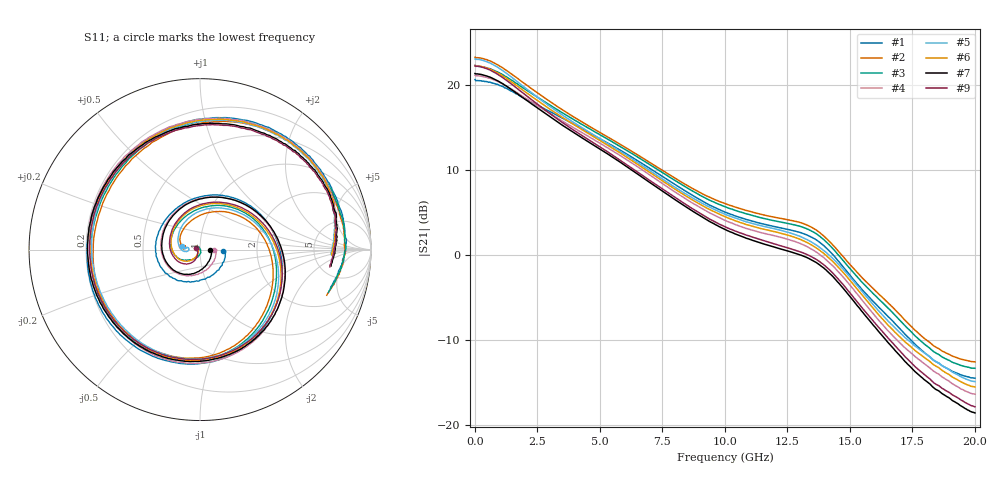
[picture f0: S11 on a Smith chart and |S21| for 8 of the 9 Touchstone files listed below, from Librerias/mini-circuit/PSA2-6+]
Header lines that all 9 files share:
!Keysight Technologies,N5242A,MY47200155,A.10.49.08
!Correction: S11(Full 2 Port(1,2))
!S21(Full 2 Port(1,2))
!S12(Full 2 Port(1,2))
!S22(Full 2 Port(1,2))
!S2P File: Measurements: S11, S21, S12, S22:
# Hz S  dB  R 50
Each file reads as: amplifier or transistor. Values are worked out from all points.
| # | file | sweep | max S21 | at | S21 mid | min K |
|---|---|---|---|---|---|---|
| 1 | PSA2-6+_Minus45DegC_+4.75V_Unit1.s2p | 10 MHz to 20 GHz | 20.6 dB | 10 MHz | 5.2 dB at 9.85 GHz | 0.97 |
| 2 | PSA2-6+_Minus45DegC_+5.25V_Unit1.s2p | 10 MHz to 20 GHz | 23.2 dB | 10 MHz | 6.2 dB at 9.85 GHz | 1.02 |
| 3 | PSA2-6+_Minus45DegC_+5V_Unit1.s2p | 10 MHz to 20 GHz | 22.3 dB | 10 MHz | 5.9 dB at 9.85 GHz | 1.02 |
| 4 | PSA2-6+_Plus25DegC_+4.75V_Unit1.s2p | 10 MHz to 20 GHz | 21.1 dB | 10 MHz | 4.3 dB at 9.85 GHz | 1.00 |
| 5 | PSA2-6+_Plus25DegC_+5.25V_Unit1.s2p | 10 MHz to 20 GHz | 23.0 dB | 20 MHz | 5.0 dB at 9.85 GHz | 1.02 |
| 6 | PSA2-6+_Plus25DegC_+5V_Unit1.s2p | 10 MHz to 20 GHz | 22.3 dB | 10 MHz | 4.7 dB at 9.85 GHz | 1.02 |
| 7 | PSA2-6+_Plus85DegC_+4.75V_Unit1.s2p | 10 MHz to 20 GHz | 21.3 dB | 10 MHz | 3.2 dB at 9.85 GHz | 1.02 |
| 8 | PSA2-6+_Plus85DegC_+5.25V_Unit1.s2p | 20 MHz to 20 GHz | 22.9 dB | 20 MHz | 3.8 dB at 9.85 GHz | 1.02 |
| 9 | PSA2-6+_Plus85DegC_+5V_Unit1.s2p | 10 MHz to 20 GHz | 22.2 dB | 20 MHz | 3.5 dB at 9.85 GHz | 1.02 |
